VERSION 5.8 ;
BUSBITCHARS "[]" ;
DIVIDERCHAR "/" ;
UNITS
    DATABASE MICRONS 1000 ;
END UNITS

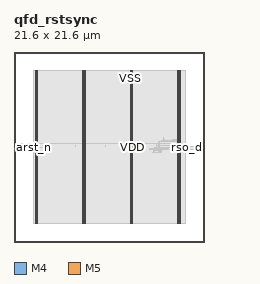
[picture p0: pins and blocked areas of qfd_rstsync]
MACRO qfd_rstsync
  FOREIGN qfd_rstsync 0 0 ;
  CLASS BLOCK ;
  SIZE 21.6 BY 21.6 ;
  PIN arst_n
    DIRECTION INPUT ;
    USE SIGNAL ;
    PORT
      LAYER M4 ;
        RECT  0 10.704 0.084 10.728 ;
    END
  END arst_n
  PIN ck
    DIRECTION INPUT ;
    USE SIGNAL ;
    PORT
      LAYER M4 ;
        RECT  0 10.8 0.084 10.824 ;
    END
  END ck
  PIN rso_d
    DIRECTION OUTPUT ;
    USE SIGNAL ;
    PORT
      LAYER M4 ;
        RECT  21.516 10.704 21.6 10.728 ;
    END
  END rso_d
  PIN rso_f
    DIRECTION OUTPUT ;
    USE SIGNAL ;
    PORT
      LAYER M4 ;
        RECT  21.516 10.8 21.6 10.824 ;
    END
  END rso_f
  PIN VDD
    DIRECTION INOUT ;
    USE POWER ;
    PORT
      LAYER M5 ;
        RECT  18.792 2.151 18.912 19.449 ;
        RECT  13.392 2.151 13.512 19.449 ;
        RECT  7.992 2.151 8.112 19.449 ;
        RECT  2.592 2.151 2.712 19.449 ;
    END
  END VDD
  PIN VSS
    DIRECTION INOUT ;
    USE GROUND ;
    PORT
      LAYER M5 ;
        RECT  18.6 2.137 18.72 19.463 ;
        RECT  13.2 2.137 13.32 19.463 ;
        RECT  7.8 2.137 7.92 19.463 ;
        RECT  2.4 2.137 2.52 19.463 ;
    END
  END VSS
  # OT_OBS_CLOSED layer=M5 d_um=1.536 added=0
  OBS
    LAYER RVTN ;
     RECT  2.16 2.16 19.44 2.295 ;
     RECT  2.16 2.565 19.44 2.835 ;
     RECT  2.16 3.105 19.44 3.375 ;
     RECT  2.16 3.645 19.44 3.915 ;
     RECT  2.16 4.185 19.44 4.455 ;
     RECT  2.16 4.725 19.44 4.995 ;
     RECT  2.16 5.265 19.44 5.535 ;
     RECT  2.16 5.805 19.44 6.075 ;
     RECT  2.16 6.345 19.44 6.615 ;
     RECT  2.16 6.885 19.44 7.155 ;
     RECT  2.16 7.425 19.44 7.695 ;
     RECT  2.16 7.965 19.44 8.235 ;
     RECT  2.16 8.505 19.44 8.775 ;
     RECT  2.16 9.045 19.44 9.315 ;
     RECT  2.16 9.585 19.44 9.855 ;
     RECT  2.16 10.125 19.44 10.395 ;
     RECT  2.16 10.665 19.44 10.935 ;
     RECT  2.16 11.205 19.44 11.475 ;
     RECT  2.16 11.745 19.44 12.015 ;
     RECT  2.16 12.285 19.44 12.555 ;
     RECT  2.16 12.825 19.44 13.095 ;
     RECT  2.16 13.365 19.44 13.635 ;
     RECT  2.16 13.905 19.44 14.175 ;
     RECT  2.16 14.445 19.44 14.715 ;
     RECT  2.16 14.985 19.44 15.255 ;
     RECT  2.16 15.525 19.44 15.795 ;
     RECT  2.16 16.065 19.44 16.335 ;
     RECT  2.16 16.605 19.44 16.875 ;
     RECT  2.16 17.145 19.44 17.415 ;
     RECT  2.16 17.685 19.44 17.955 ;
     RECT  2.16 18.225 19.44 18.495 ;
     RECT  2.16 18.765 19.44 19.035 ;
     RECT  2.16 19.305 19.44 19.44 ;
    LAYER RVTP ;
     RECT  2.16 2.295 19.44 2.565 ;
     RECT  2.16 2.835 19.44 3.105 ;
     RECT  2.16 3.375 19.44 3.645 ;
     RECT  2.16 3.915 19.44 4.185 ;
     RECT  2.16 4.455 19.44 4.725 ;
     RECT  2.16 4.995 19.44 5.265 ;
     RECT  2.16 5.535 19.44 5.805 ;
     RECT  2.16 6.075 19.44 6.345 ;
     RECT  2.16 6.615 19.44 6.885 ;
     RECT  2.16 7.155 19.44 7.425 ;
     RECT  2.16 7.695 19.44 7.965 ;
     RECT  2.16 8.235 19.44 8.505 ;
     RECT  2.16 8.775 19.44 9.045 ;
     RECT  2.16 9.315 19.44 9.585 ;
     RECT  2.16 9.855 19.44 10.125 ;
     RECT  2.16 10.395 19.44 10.665 ;
     RECT  2.16 10.935 19.44 11.205 ;
     RECT  2.16 11.475 19.44 11.745 ;
     RECT  2.16 12.015 19.44 12.285 ;
     RECT  2.16 12.555 19.44 12.825 ;
     RECT  2.16 13.095 19.44 13.365 ;
     RECT  2.16 13.635 19.44 13.905 ;
     RECT  2.16 14.175 19.44 14.445 ;
     RECT  2.16 14.715 19.44 14.985 ;
     RECT  2.16 15.255 19.44 15.525 ;
     RECT  2.16 15.795 19.44 16.065 ;
     RECT  2.16 16.335 19.44 16.605 ;
     RECT  2.16 16.875 19.44 17.145 ;
     RECT  2.16 17.415 19.44 17.685 ;
     RECT  2.16 17.955 19.44 18.225 ;
     RECT  2.16 18.495 19.44 18.765 ;
     RECT  2.16 19.035 19.44 19.305 ;
    LAYER M1 ;
     RECT  2.16 2.151 19.44 19.449 ;
    LAYER M2 ;
     RECT  2.16 2.151 19.44 19.449 ;
     RECT  19.44 10.476 20.507 10.854 ;
    LAYER M3 ;
     RECT  2.415 2.143 2.505 2.413 ;
     RECT  7.815 2.143 7.905 2.413 ;
     RECT  13.215 2.143 13.305 2.413 ;
     RECT  18.615 2.143 18.705 2.413 ;
     RECT  15.804 10.165 15.822 10.201 ;
     RECT  16.704 10.165 16.722 10.201 ;
     RECT  18.615 2.413 18.897 10.291 ;
     RECT  15.804 10.201 15.966 10.399 ;
     RECT  16.704 10.201 16.794 10.399 ;
     RECT  15.804 10.399 16.794 10.471 ;
     RECT  15.444 10.471 17.514 10.661 ;
     RECT  13.215 2.413 13.497 10.705 ;
     RECT  15.984 10.661 17.514 10.741 ;
     RECT  18.615 10.291 19.098 10.741 ;
     RECT  15.984 10.741 19.098 10.769 ;
     RECT  13.215 10.705 13.806 10.859 ;
     RECT  20.484 10.471 20.502 10.859 ;
     RECT  3.492 10.699 3.51 10.895 ;
     RECT  10.44 10.831 10.458 10.931 ;
     RECT  16.164 10.769 19.098 10.931 ;
     RECT  6.948 10.831 6.966 11.003 ;
     RECT  16.164 10.931 18.897 11.213 ;
     RECT  16.488 11.213 18.897 11.453 ;
     RECT  16.776 11.453 18.897 11.543 ;
     RECT  16.776 11.543 17.118 11.579 ;
     RECT  16.956 11.579 17.118 11.705 ;
     RECT  17.964 11.543 18.897 11.705 ;
     RECT  16.956 11.705 16.974 11.849 ;
     RECT  2.415 2.413 2.697 19.187 ;
     RECT  7.815 2.413 8.097 19.187 ;
     RECT  13.215 10.859 13.497 19.187 ;
     RECT  18.615 11.705 18.897 19.187 ;
     RECT  2.415 19.187 2.505 19.457 ;
     RECT  7.815 19.187 7.905 19.457 ;
     RECT  13.215 19.187 13.305 19.457 ;
     RECT  18.615 19.187 18.705 19.457 ;
    LAYER M4 ;
     RECT  0.06 10.704 0.133 10.824 ;
     RECT  0.133 10.704 2.408 11.208 ;
     RECT  2.408 2.148 2.512 19.452 ;
     RECT  2.512 2.418 2.704 19.182 ;
     RECT  2.704 10.704 3.521 11.208 ;
     RECT  3.521 11.184 7.808 11.208 ;
     RECT  7.808 2.148 7.912 19.452 ;
     RECT  7.912 2.418 8.104 19.182 ;
     RECT  8.104 11.184 13.208 11.208 ;
     RECT  13.208 2.148 13.312 19.452 ;
     RECT  13.312 2.418 13.504 19.182 ;
     RECT  13.504 11.184 16.193 11.208 ;
     RECT  15.793 10.176 16.499 10.2 ;
     RECT  16.413 11.424 17.129 11.448 ;
     RECT  18.608 2.148 18.712 19.452 ;
     RECT  18.712 2.418 18.904 19.182 ;
     RECT  20.473 10.704 21.564 10.824 ;
    LAYER M5 ;
     RECT  2.4 2.137 2.52 2.151 ;
     RECT  7.8 2.137 7.92 2.151 ;
     RECT  13.2 2.137 13.32 2.151 ;
     RECT  18.6 2.137 18.72 2.151 ;
     RECT  0.144 10.789 0.168 11.219 ;
     RECT  16.464 10.165 16.488 11.459 ;
     RECT  2.4 2.151 2.712 19.449 ;
     RECT  7.8 2.151 8.112 19.449 ;
     RECT  13.2 2.151 13.512 19.449 ;
     RECT  18.6 2.151 18.912 19.449 ;
     RECT  2.4 19.449 2.52 19.463 ;
     RECT  7.8 19.449 7.92 19.463 ;
     RECT  13.2 19.449 13.32 19.463 ;
     RECT  18.6 19.449 18.72 19.463 ;
  END
END qfd_rstsync
END LIBRARY
